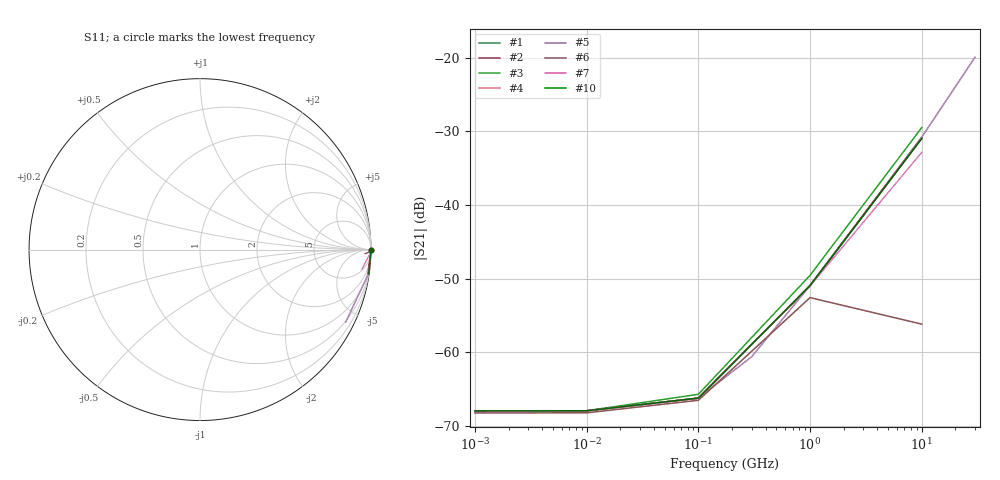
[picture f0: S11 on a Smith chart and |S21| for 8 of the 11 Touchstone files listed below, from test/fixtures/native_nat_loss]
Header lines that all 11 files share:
! Sonnet Data File
! From: em Version : 18.53-Lite
! Data is NOT De-embedded
# GHZ S RI R 50.00000
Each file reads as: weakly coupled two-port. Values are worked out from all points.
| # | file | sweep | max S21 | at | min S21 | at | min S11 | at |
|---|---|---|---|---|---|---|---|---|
| 1 | n1f.native.s2p | 1 MHz to 10 GHz | -30.90 dB | 10 GHz | -68.0 dB | 1 MHz | 0.0 dB | 10 GHz |
| 2 | nat_ni.native.s2p | 1 MHz to 10 GHz | -30.81 dB | 10 GHz | -68.0 dB | 1 MHz | 0.0 dB | 10 GHz |
| 3 | natcinf.native.s2p | 1 MHz to 10 GHz | -29.51 dB | 10 GHz | -68.0 dB | 1 MHz | 0.0 dB | 10 GHz |
| 4 | natcov.native.s2p | 1 MHz to 10 GHz | -30.98 dB | 10 GHz | -68.0 dB | 1 MHz | -0.1 dB | 10 GHz |
| 5 | natw.native.s2p | 1 MHz to 30 GHz | -19.96 dB | 30 GHz | -68.0 dB | 1 MHz | -0.4 dB | 30 GHz |
| 6 | nd_1e3.native.s2p | 1 MHz to 10 GHz | -52.58 dB | 1 GHz | -68.2 dB | 1 MHz | -0.3 dB | 10 GHz |
| 7 | nd_100.native.s2p | 1 MHz to 10 GHz | -32.87 dB | 10 GHz | -68.0 dB | 1 MHz | -0.4 dB | 10 GHz |
| 8 | nd_500.native.s2p | 1 MHz to 10 GHz | -45.47 dB | 10 GHz | -68.1 dB | 1 MHz | -0.4 dB | 10 GHz |
| 9 | nd_var.native.s2p | 1 MHz to 10 GHz | -30.90 dB | 10 GHz | -68.0 dB | 1 MHz | 0.0 dB | 10 GHz |
| 10 | nneg1.native.s2p | 1 MHz to 10 GHz | -31.00 dB | 10 GHz | -68.0 dB | 1 MHz | 0.0 dB | 10 GHz |
| 11 | nz1.native.s2p | 1 MHz to 10 GHz | -30.81 dB | 10 GHz | -68.0 dB | 1 MHz | 0.0 dB | 10 GHz |
